VERSION 5.7 ;
  NOWIREEXTENSIONATPIN ON ;
  DIVIDERCHAR "/" ;
  BUSBITCHARS "[]" ;
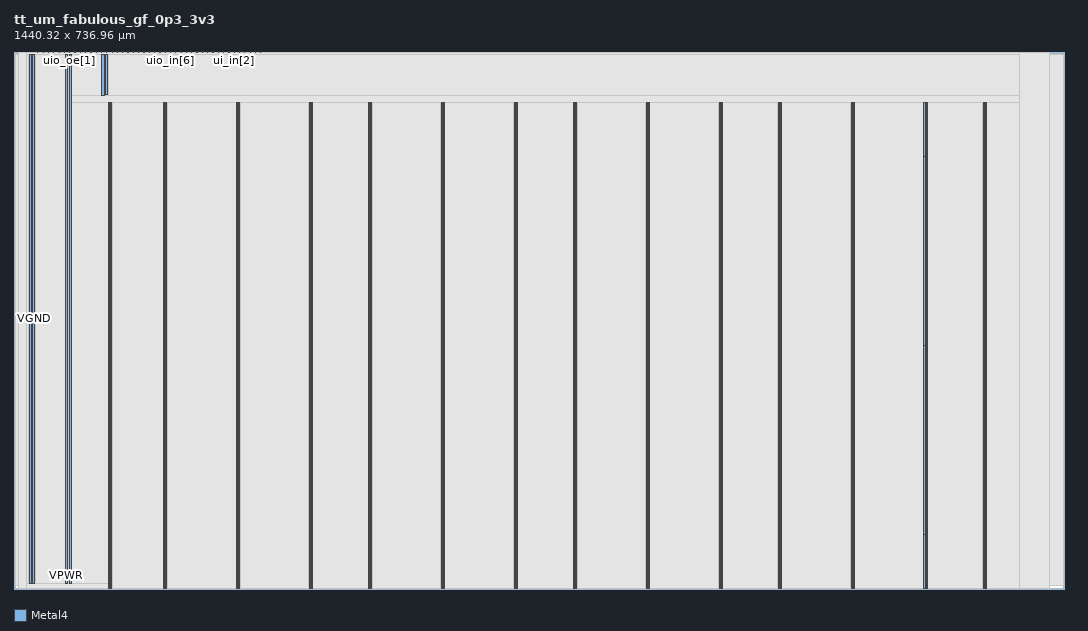
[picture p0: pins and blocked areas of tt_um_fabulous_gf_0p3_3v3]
MACRO tt_um_fabulous_gf_0p3_3v3
  CLASS BLOCK ;
  FOREIGN tt_um_fabulous_gf_0p3_3v3 ;
  ORIGIN 0.000 0.000 ;
  SIZE 1440.320 BY 736.960 ;
  PIN VGND
    DIRECTION INOUT ;
    USE GROUND ;
    PORT
      LAYER Metal4 ;
        RECT 132.580 592.600 134.180 667.080 ;
    END
    PORT
      LAYER Metal4 ;
        RECT 132.580 333.880 134.180 592.600 ;
    END
    PORT
      LAYER Metal4 ;
        RECT 132.580 75.160 134.180 333.880 ;
    END
    PORT
      LAYER Metal4 ;
        RECT 132.580 0.680 134.180 75.160 ;
    END
    PORT
      LAYER Metal4 ;
        RECT 208.180 592.600 209.780 667.080 ;
    END
    PORT
      LAYER Metal4 ;
        RECT 308.180 592.600 309.780 667.080 ;
    END
    PORT
      LAYER Metal4 ;
        RECT 408.180 592.600 409.780 667.080 ;
    END
    PORT
      LAYER Metal4 ;
        RECT 208.180 333.880 209.780 592.600 ;
    END
    PORT
      LAYER Metal4 ;
        RECT 308.180 333.880 309.780 592.600 ;
    END
    PORT
      LAYER Metal4 ;
        RECT 408.180 333.880 409.780 592.600 ;
    END
    PORT
      LAYER Metal4 ;
        RECT 208.180 75.160 209.780 333.880 ;
    END
    PORT
      LAYER Metal4 ;
        RECT 308.180 75.160 309.780 333.880 ;
    END
    PORT
      LAYER Metal4 ;
        RECT 408.180 75.160 409.780 333.880 ;
    END
    PORT
      LAYER Metal4 ;
        RECT 208.180 0.680 209.780 75.160 ;
    END
    PORT
      LAYER Metal4 ;
        RECT 308.180 0.680 309.780 75.160 ;
    END
    PORT
      LAYER Metal4 ;
        RECT 408.180 0.680 409.780 75.160 ;
    END
    PORT
      LAYER Metal4 ;
        RECT 489.300 592.600 490.900 667.080 ;
    END
    PORT
      LAYER Metal4 ;
        RECT 589.300 592.600 590.900 667.080 ;
    END
    PORT
      LAYER Metal4 ;
        RECT 689.300 592.600 690.900 667.080 ;
    END
    PORT
      LAYER Metal4 ;
        RECT 489.300 333.880 490.900 592.600 ;
    END
    PORT
      LAYER Metal4 ;
        RECT 589.300 333.880 590.900 592.600 ;
    END
    PORT
      LAYER Metal4 ;
        RECT 689.300 333.880 690.900 592.600 ;
    END
    PORT
      LAYER Metal4 ;
        RECT 489.300 75.160 490.900 333.880 ;
    END
    PORT
      LAYER Metal4 ;
        RECT 589.300 75.160 590.900 333.880 ;
    END
    PORT
      LAYER Metal4 ;
        RECT 689.300 75.160 690.900 333.880 ;
    END
    PORT
      LAYER Metal4 ;
        RECT 489.300 0.680 490.900 75.160 ;
    END
    PORT
      LAYER Metal4 ;
        RECT 589.300 0.680 590.900 75.160 ;
    END
    PORT
      LAYER Metal4 ;
        RECT 689.300 0.680 690.900 75.160 ;
    END
    PORT
      LAYER Metal4 ;
        RECT 770.420 592.600 772.020 667.080 ;
    END
    PORT
      LAYER Metal4 ;
        RECT 870.420 592.600 872.020 667.080 ;
    END
    PORT
      LAYER Metal4 ;
        RECT 970.420 592.600 972.020 667.080 ;
    END
    PORT
      LAYER Metal4 ;
        RECT 770.420 333.880 772.020 592.600 ;
    END
    PORT
      LAYER Metal4 ;
        RECT 870.420 333.880 872.020 592.600 ;
    END
    PORT
      LAYER Metal4 ;
        RECT 970.420 333.880 972.020 592.600 ;
    END
    PORT
      LAYER Metal4 ;
        RECT 770.420 75.160 772.020 333.880 ;
    END
    PORT
      LAYER Metal4 ;
        RECT 870.420 75.160 872.020 333.880 ;
    END
    PORT
      LAYER Metal4 ;
        RECT 970.420 75.160 972.020 333.880 ;
    END
    PORT
      LAYER Metal4 ;
        RECT 770.420 0.680 772.020 75.160 ;
    END
    PORT
      LAYER Metal4 ;
        RECT 870.420 0.680 872.020 75.160 ;
    END
    PORT
      LAYER Metal4 ;
        RECT 970.420 0.680 972.020 75.160 ;
    END
    PORT
      LAYER Metal4 ;
        RECT 1051.540 592.600 1053.140 667.080 ;
    END
    PORT
      LAYER Metal4 ;
        RECT 1151.540 592.600 1153.140 667.080 ;
    END
    PORT
      LAYER Metal4 ;
        RECT 1251.540 592.600 1253.140 667.080 ;
    END
    PORT
      LAYER Metal4 ;
        RECT 1051.540 333.880 1053.140 592.600 ;
    END
    PORT
      LAYER Metal4 ;
        RECT 1151.540 333.880 1153.140 592.600 ;
    END
    PORT
      LAYER Metal4 ;
        RECT 1251.540 333.880 1253.140 592.600 ;
    END
    PORT
      LAYER Metal4 ;
        RECT 1051.540 75.160 1053.140 333.880 ;
    END
    PORT
      LAYER Metal4 ;
        RECT 1151.540 75.160 1153.140 333.880 ;
    END
    PORT
      LAYER Metal4 ;
        RECT 1251.540 75.160 1253.140 333.880 ;
    END
    PORT
      LAYER Metal4 ;
        RECT 1051.540 0.680 1053.140 75.160 ;
    END
    PORT
      LAYER Metal4 ;
        RECT 1151.540 0.680 1153.140 75.160 ;
    END
    PORT
      LAYER Metal4 ;
        RECT 1251.540 0.680 1253.140 75.160 ;
    END
    PORT
      LAYER Metal4 ;
        RECT 1332.660 592.600 1334.260 667.080 ;
    END
    PORT
      LAYER Metal4 ;
        RECT 1332.660 333.880 1334.260 592.600 ;
    END
    PORT
      LAYER Metal4 ;
        RECT 1332.660 75.160 1334.260 333.880 ;
    END
    PORT
      LAYER Metal4 ;
        RECT 1332.660 0.680 1334.260 75.160 ;
    END
    PORT
      LAYER Metal4 ;
        RECT 25.540 7.540 28.740 733.340 ;
    END
    PORT
      LAYER Metal4 ;
        RECT 75.540 7.540 78.740 733.340 ;
    END
    PORT
      LAYER Metal4 ;
        RECT 125.540 677.640 128.740 733.340 ;
    END
  END VGND
  PIN VPWR
    DIRECTION INOUT ;
    USE POWER ;
    PORT
      LAYER Metal4 ;
        RECT 129.280 592.600 130.880 667.080 ;
    END
    PORT
      LAYER Metal4 ;
        RECT 129.280 333.880 130.880 592.600 ;
    END
    PORT
      LAYER Metal4 ;
        RECT 129.280 75.160 130.880 333.880 ;
    END
    PORT
      LAYER Metal4 ;
        RECT 129.280 0.680 130.880 75.160 ;
    END
    PORT
      LAYER Metal4 ;
        RECT 204.880 592.600 206.480 667.080 ;
    END
    PORT
      LAYER Metal4 ;
        RECT 304.880 592.600 306.480 667.080 ;
    END
    PORT
      LAYER Metal4 ;
        RECT 404.880 592.600 406.480 667.080 ;
    END
    PORT
      LAYER Metal4 ;
        RECT 204.880 333.880 206.480 592.600 ;
    END
    PORT
      LAYER Metal4 ;
        RECT 304.880 333.880 306.480 592.600 ;
    END
    PORT
      LAYER Metal4 ;
        RECT 404.880 333.880 406.480 592.600 ;
    END
    PORT
      LAYER Metal4 ;
        RECT 204.880 75.160 206.480 333.880 ;
    END
    PORT
      LAYER Metal4 ;
        RECT 304.880 75.160 306.480 333.880 ;
    END
    PORT
      LAYER Metal4 ;
        RECT 404.880 75.160 406.480 333.880 ;
    END
    PORT
      LAYER Metal4 ;
        RECT 204.880 0.680 206.480 75.160 ;
    END
    PORT
      LAYER Metal4 ;
        RECT 304.880 0.680 306.480 75.160 ;
    END
    PORT
      LAYER Metal4 ;
        RECT 404.880 0.680 406.480 75.160 ;
    END
    PORT
      LAYER Metal4 ;
        RECT 486.000 592.600 487.600 667.080 ;
    END
    PORT
      LAYER Metal4 ;
        RECT 586.000 592.600 587.600 667.080 ;
    END
    PORT
      LAYER Metal4 ;
        RECT 686.000 592.600 687.600 667.080 ;
    END
    PORT
      LAYER Metal4 ;
        RECT 486.000 333.880 487.600 592.600 ;
    END
    PORT
      LAYER Metal4 ;
        RECT 586.000 333.880 587.600 592.600 ;
    END
    PORT
      LAYER Metal4 ;
        RECT 686.000 333.880 687.600 592.600 ;
    END
    PORT
      LAYER Metal4 ;
        RECT 486.000 75.160 487.600 333.880 ;
    END
    PORT
      LAYER Metal4 ;
        RECT 586.000 75.160 587.600 333.880 ;
    END
    PORT
      LAYER Metal4 ;
        RECT 686.000 75.160 687.600 333.880 ;
    END
    PORT
      LAYER Metal4 ;
        RECT 486.000 0.680 487.600 75.160 ;
    END
    PORT
      LAYER Metal4 ;
        RECT 586.000 0.680 587.600 75.160 ;
    END
    PORT
      LAYER Metal4 ;
        RECT 686.000 0.680 687.600 75.160 ;
    END
    PORT
      LAYER Metal4 ;
        RECT 767.120 592.600 768.720 667.080 ;
    END
    PORT
      LAYER Metal4 ;
        RECT 867.120 592.600 868.720 667.080 ;
    END
    PORT
      LAYER Metal4 ;
        RECT 967.120 592.600 968.720 667.080 ;
    END
    PORT
      LAYER Metal4 ;
        RECT 767.120 333.880 768.720 592.600 ;
    END
    PORT
      LAYER Metal4 ;
        RECT 867.120 333.880 868.720 592.600 ;
    END
    PORT
      LAYER Metal4 ;
        RECT 967.120 333.880 968.720 592.600 ;
    END
    PORT
      LAYER Metal4 ;
        RECT 767.120 75.160 768.720 333.880 ;
    END
    PORT
      LAYER Metal4 ;
        RECT 867.120 75.160 868.720 333.880 ;
    END
    PORT
      LAYER Metal4 ;
        RECT 967.120 75.160 968.720 333.880 ;
    END
    PORT
      LAYER Metal4 ;
        RECT 767.120 0.680 768.720 75.160 ;
    END
    PORT
      LAYER Metal4 ;
        RECT 867.120 0.680 868.720 75.160 ;
    END
    PORT
      LAYER Metal4 ;
        RECT 967.120 0.680 968.720 75.160 ;
    END
    PORT
      LAYER Metal4 ;
        RECT 1048.240 592.600 1049.840 667.080 ;
    END
    PORT
      LAYER Metal4 ;
        RECT 1148.240 592.600 1149.840 667.080 ;
    END
    PORT
      LAYER Metal4 ;
        RECT 1248.240 592.600 1249.840 667.080 ;
    END
    PORT
      LAYER Metal4 ;
        RECT 1048.240 333.880 1049.840 592.600 ;
    END
    PORT
      LAYER Metal4 ;
        RECT 1148.240 333.880 1149.840 592.600 ;
    END
    PORT
      LAYER Metal4 ;
        RECT 1248.240 333.880 1249.840 592.600 ;
    END
    PORT
      LAYER Metal4 ;
        RECT 1048.240 75.160 1049.840 333.880 ;
    END
    PORT
      LAYER Metal4 ;
        RECT 1148.240 75.160 1149.840 333.880 ;
    END
    PORT
      LAYER Metal4 ;
        RECT 1248.240 75.160 1249.840 333.880 ;
    END
    PORT
      LAYER Metal4 ;
        RECT 1048.240 0.680 1049.840 75.160 ;
    END
    PORT
      LAYER Metal4 ;
        RECT 1148.240 0.680 1149.840 75.160 ;
    END
    PORT
      LAYER Metal4 ;
        RECT 1248.240 0.680 1249.840 75.160 ;
    END
    PORT
      LAYER Metal4 ;
        RECT 1329.360 592.600 1330.960 667.080 ;
    END
    PORT
      LAYER Metal4 ;
        RECT 1329.360 333.880 1330.960 592.600 ;
    END
    PORT
      LAYER Metal4 ;
        RECT 1329.360 75.160 1330.960 333.880 ;
    END
    PORT
      LAYER Metal4 ;
        RECT 1329.360 0.680 1330.960 75.160 ;
    END
    PORT
      LAYER Metal4 ;
        RECT 20.640 7.540 23.840 733.340 ;
    END
    PORT
      LAYER Metal4 ;
        RECT 70.640 7.540 73.840 733.340 ;
    END
    PORT
      LAYER Metal4 ;
        RECT 120.640 676.710 123.840 733.340 ;
    END
  END VPWR
  PIN clk
    DIRECTION INPUT ;
    USE SIGNAL ;
    ANTENNAGATEAREA 4.704000 ;
    ANTENNADIFFAREA 0.877000 ;
    PORT
      LAYER Metal4 ;
        RECT 331.090 735.960 331.390 736.960 ;
    END
  END clk
  PIN ena
    DIRECTION INPUT ;
    USE SIGNAL ;
    PORT
      LAYER Metal4 ;
        RECT 338.370 735.960 338.670 736.960 ;
    END
  END ena
  PIN rst_n
    DIRECTION INPUT ;
    USE SIGNAL ;
    ANTENNAGATEAREA 0.666400 ;
    ANTENNADIFFAREA 0.438500 ;
    PORT
      LAYER Metal4 ;
        RECT 323.810 735.960 324.110 736.960 ;
    END
  END rst_n
  PIN ui_in[0]
    DIRECTION INPUT ;
    USE SIGNAL ;
    ANTENNAGATEAREA 0.666400 ;
    ANTENNADIFFAREA 0.438500 ;
    PORT
      LAYER Metal4 ;
        RECT 316.530 735.960 316.830 736.960 ;
    END
  END ui_in[0]
  PIN ui_in[1]
    DIRECTION INPUT ;
    USE SIGNAL ;
    ANTENNAGATEAREA 0.666400 ;
    ANTENNADIFFAREA 0.438500 ;
    PORT
      LAYER Metal4 ;
        RECT 309.250 735.960 309.550 736.960 ;
    END
  END ui_in[1]
  PIN ui_in[2]
    DIRECTION INPUT ;
    USE SIGNAL ;
    ANTENNAGATEAREA 1.332800 ;
    ANTENNADIFFAREA 0.438500 ;
    PORT
      LAYER Metal4 ;
        RECT 301.970 735.960 302.270 736.960 ;
    END
  END ui_in[2]
  PIN ui_in[3]
    DIRECTION INPUT ;
    USE SIGNAL ;
    ANTENNAGATEAREA 1.332800 ;
    ANTENNADIFFAREA 0.438500 ;
    PORT
      LAYER Metal4 ;
        RECT 294.690 735.960 294.990 736.960 ;
    END
  END ui_in[3]
  PIN ui_in[4]
    DIRECTION INPUT ;
    USE SIGNAL ;
    ANTENNAGATEAREA 1.332800 ;
    ANTENNADIFFAREA 0.438500 ;
    PORT
      LAYER Metal4 ;
        RECT 287.410 735.960 287.710 736.960 ;
    END
  END ui_in[4]
  PIN ui_in[5]
    DIRECTION INPUT ;
    USE SIGNAL ;
    ANTENNAGATEAREA 1.332800 ;
    ANTENNADIFFAREA 0.438500 ;
    PORT
      LAYER Metal4 ;
        RECT 280.130 735.960 280.430 736.960 ;
    END
  END ui_in[5]
  PIN ui_in[6]
    DIRECTION INPUT ;
    USE SIGNAL ;
    ANTENNAGATEAREA 1.332800 ;
    ANTENNADIFFAREA 0.438500 ;
    PORT
      LAYER Metal4 ;
        RECT 272.850 735.960 273.150 736.960 ;
    END
  END ui_in[6]
  PIN ui_in[7]
    DIRECTION INPUT ;
    USE SIGNAL ;
    ANTENNAGATEAREA 1.332800 ;
    ANTENNADIFFAREA 0.438500 ;
    PORT
      LAYER Metal4 ;
        RECT 265.570 735.960 265.870 736.960 ;
    END
  END ui_in[7]
  PIN uio_in[0]
    DIRECTION INPUT ;
    USE SIGNAL ;
    ANTENNAGATEAREA 1.332800 ;
    ANTENNADIFFAREA 0.438500 ;
    PORT
      LAYER Metal4 ;
        RECT 258.290 735.960 258.590 736.960 ;
    END
  END uio_in[0]
  PIN uio_in[1]
    DIRECTION INPUT ;
    USE SIGNAL ;
    ANTENNAGATEAREA 1.332800 ;
    ANTENNADIFFAREA 0.438500 ;
    PORT
      LAYER Metal4 ;
        RECT 251.010 735.960 251.310 736.960 ;
    END
  END uio_in[1]
  PIN uio_in[2]
    DIRECTION INPUT ;
    USE SIGNAL ;
    ANTENNAGATEAREA 1.332800 ;
    ANTENNADIFFAREA 0.438500 ;
    PORT
      LAYER Metal4 ;
        RECT 243.730 735.960 244.030 736.960 ;
    END
  END uio_in[2]
  PIN uio_in[3]
    DIRECTION INPUT ;
    USE SIGNAL ;
    ANTENNAGATEAREA 1.332800 ;
    ANTENNADIFFAREA 0.438500 ;
    PORT
      LAYER Metal4 ;
        RECT 236.450 735.960 236.750 736.960 ;
    END
  END uio_in[3]
  PIN uio_in[4]
    DIRECTION INPUT ;
    USE SIGNAL ;
    ANTENNAGATEAREA 1.332800 ;
    ANTENNADIFFAREA 0.438500 ;
    PORT
      LAYER Metal4 ;
        RECT 229.170 735.960 229.470 736.960 ;
    END
  END uio_in[4]
  PIN uio_in[5]
    DIRECTION INPUT ;
    USE SIGNAL ;
    ANTENNAGATEAREA 1.332800 ;
    ANTENNADIFFAREA 0.438500 ;
    PORT
      LAYER Metal4 ;
        RECT 221.890 735.960 222.190 736.960 ;
    END
  END uio_in[5]
  PIN uio_in[6]
    DIRECTION INPUT ;
    USE SIGNAL ;
    ANTENNAGATEAREA 1.332800 ;
    ANTENNADIFFAREA 0.438500 ;
    PORT
      LAYER Metal4 ;
        RECT 214.610 735.960 214.910 736.960 ;
    END
  END uio_in[6]
  PIN uio_in[7]
    DIRECTION INPUT ;
    USE SIGNAL ;
    ANTENNAGATEAREA 1.332800 ;
    ANTENNADIFFAREA 0.438500 ;
    PORT
      LAYER Metal4 ;
        RECT 207.330 735.960 207.630 736.960 ;
    END
  END uio_in[7]
  PIN uio_oe[0]
    DIRECTION OUTPUT ;
    USE SIGNAL ;
    ANTENNADIFFAREA 1.676100 ;
    PORT
      LAYER Metal4 ;
        RECT 83.570 735.960 83.870 736.960 ;
    END
  END uio_oe[0]
  PIN uio_oe[1]
    DIRECTION OUTPUT ;
    USE SIGNAL ;
    ANTENNADIFFAREA 1.676100 ;
    PORT
      LAYER Metal4 ;
        RECT 76.290 735.960 76.590 736.960 ;
    END
  END uio_oe[1]
  PIN uio_oe[2]
    DIRECTION OUTPUT ;
    USE SIGNAL ;
    ANTENNADIFFAREA 1.676100 ;
    PORT
      LAYER Metal4 ;
        RECT 69.010 735.960 69.310 736.960 ;
    END
  END uio_oe[2]
  PIN uio_oe[3]
    DIRECTION OUTPUT ;
    USE SIGNAL ;
    ANTENNADIFFAREA 1.676100 ;
    PORT
      LAYER Metal4 ;
        RECT 61.730 735.960 62.030 736.960 ;
    END
  END uio_oe[3]
  PIN uio_oe[4]
    DIRECTION OUTPUT ;
    USE SIGNAL ;
    ANTENNADIFFAREA 1.676100 ;
    PORT
      LAYER Metal4 ;
        RECT 54.450 735.960 54.750 736.960 ;
    END
  END uio_oe[4]
  PIN uio_oe[5]
    DIRECTION OUTPUT ;
    USE SIGNAL ;
    ANTENNADIFFAREA 1.676100 ;
    PORT
      LAYER Metal4 ;
        RECT 47.170 735.960 47.470 736.960 ;
    END
  END uio_oe[5]
  PIN uio_oe[6]
    DIRECTION OUTPUT ;
    USE SIGNAL ;
    ANTENNADIFFAREA 1.676100 ;
    PORT
      LAYER Metal4 ;
        RECT 39.890 735.960 40.190 736.960 ;
    END
  END uio_oe[6]
  PIN uio_oe[7]
    DIRECTION OUTPUT ;
    USE SIGNAL ;
    ANTENNADIFFAREA 1.676100 ;
    PORT
      LAYER Metal4 ;
        RECT 32.610 735.960 32.910 736.960 ;
    END
  END uio_oe[7]
  PIN uio_out[0]
    DIRECTION OUTPUT ;
    USE SIGNAL ;
    ANTENNADIFFAREA 1.676100 ;
    PORT
      LAYER Metal4 ;
        RECT 141.810 735.960 142.110 736.960 ;
    END
  END uio_out[0]
  PIN uio_out[1]
    DIRECTION OUTPUT ;
    USE SIGNAL ;
    ANTENNADIFFAREA 1.676100 ;
    PORT
      LAYER Metal4 ;
        RECT 134.530 735.960 134.830 736.960 ;
    END
  END uio_out[1]
  PIN uio_out[2]
    DIRECTION OUTPUT ;
    USE SIGNAL ;
    ANTENNADIFFAREA 1.676100 ;
    PORT
      LAYER Metal4 ;
        RECT 127.250 735.960 127.550 736.960 ;
    END
  END uio_out[2]
  PIN uio_out[3]
    DIRECTION OUTPUT ;
    USE SIGNAL ;
    ANTENNADIFFAREA 1.676100 ;
    PORT
      LAYER Metal4 ;
        RECT 119.970 735.960 120.270 736.960 ;
    END
  END uio_out[3]
  PIN uio_out[4]
    DIRECTION OUTPUT ;
    USE SIGNAL ;
    ANTENNADIFFAREA 1.676100 ;
    PORT
      LAYER Metal4 ;
        RECT 112.690 735.960 112.990 736.960 ;
    END
  END uio_out[4]
  PIN uio_out[5]
    DIRECTION OUTPUT ;
    USE SIGNAL ;
    ANTENNADIFFAREA 1.676100 ;
    PORT
      LAYER Metal4 ;
        RECT 105.410 735.960 105.710 736.960 ;
    END
  END uio_out[5]
  PIN uio_out[6]
    DIRECTION OUTPUT ;
    USE SIGNAL ;
    ANTENNADIFFAREA 1.676100 ;
    PORT
      LAYER Metal4 ;
        RECT 98.130 735.960 98.430 736.960 ;
    END
  END uio_out[6]
  PIN uio_out[7]
    DIRECTION OUTPUT ;
    USE SIGNAL ;
    ANTENNADIFFAREA 1.676100 ;
    PORT
      LAYER Metal4 ;
        RECT 90.850 735.960 91.150 736.960 ;
    END
  END uio_out[7]
  PIN uo_out[0]
    DIRECTION OUTPUT ;
    USE SIGNAL ;
    ANTENNADIFFAREA 5.982500 ;
    PORT
      LAYER Metal4 ;
        RECT 200.050 735.960 200.350 736.960 ;
    END
  END uo_out[0]
  PIN uo_out[1]
    DIRECTION OUTPUT ;
    USE SIGNAL ;
    ANTENNADIFFAREA 5.982500 ;
    PORT
      LAYER Metal4 ;
        RECT 192.770 735.960 193.070 736.960 ;
    END
  END uo_out[1]
  PIN uo_out[2]
    DIRECTION OUTPUT ;
    USE SIGNAL ;
    ANTENNADIFFAREA 5.982500 ;
    PORT
      LAYER Metal4 ;
        RECT 185.490 735.960 185.790 736.960 ;
    END
  END uo_out[2]
  PIN uo_out[3]
    DIRECTION OUTPUT ;
    USE SIGNAL ;
    ANTENNADIFFAREA 5.982500 ;
    PORT
      LAYER Metal4 ;
        RECT 178.210 735.960 178.510 736.960 ;
    END
  END uo_out[3]
  PIN uo_out[4]
    DIRECTION OUTPUT ;
    USE SIGNAL ;
    ANTENNADIFFAREA 5.982500 ;
    PORT
      LAYER Metal4 ;
        RECT 170.930 735.960 171.230 736.960 ;
    END
  END uo_out[4]
  PIN uo_out[5]
    DIRECTION OUTPUT ;
    USE SIGNAL ;
    ANTENNADIFFAREA 5.982500 ;
    PORT
      LAYER Metal4 ;
        RECT 163.650 735.960 163.950 736.960 ;
    END
  END uo_out[5]
  PIN uo_out[6]
    DIRECTION OUTPUT ;
    USE SIGNAL ;
    ANTENNADIFFAREA 5.982500 ;
    PORT
      LAYER Metal4 ;
        RECT 156.370 735.960 156.670 736.960 ;
    END
  END uo_out[6]
  PIN uo_out[7]
    DIRECTION OUTPUT ;
    USE SIGNAL ;
    ANTENNADIFFAREA 5.982500 ;
    PORT
      LAYER Metal4 ;
        RECT 149.090 735.960 149.390 736.960 ;
    END
  END uo_out[7]
  OBS
      LAYER Nwell ;
        RECT 1.810 730.890 1440.190 733.470 ;
      LAYER Pwell ;
        RECT 1.810 727.350 1440.190 730.890 ;
      LAYER Nwell ;
        RECT 1.810 723.050 1440.190 727.350 ;
      LAYER Pwell ;
        RECT 1.810 719.510 1440.190 723.050 ;
      LAYER Nwell ;
        RECT 1.810 715.210 1440.190 719.510 ;
      LAYER Pwell ;
        RECT 1.810 711.670 1440.190 715.210 ;
      LAYER Nwell ;
        RECT 1.810 707.370 1440.190 711.670 ;
      LAYER Pwell ;
        RECT 1.810 703.830 1440.190 707.370 ;
      LAYER Nwell ;
        RECT 1.810 699.530 1440.190 703.830 ;
      LAYER Pwell ;
        RECT 1.810 695.990 1440.190 699.530 ;
      LAYER Nwell ;
        RECT 1.810 691.690 1440.190 695.990 ;
      LAYER Pwell ;
        RECT 1.810 688.150 1440.190 691.690 ;
      LAYER Nwell ;
        RECT 1.810 683.850 1440.190 688.150 ;
      LAYER Pwell ;
        RECT 1.810 680.310 1440.190 683.850 ;
      LAYER Nwell ;
        RECT 1.810 676.010 1440.190 680.310 ;
      LAYER Pwell ;
        RECT 1.810 673.810 1440.190 676.010 ;
        RECT 1.810 672.470 106.270 673.810 ;
      LAYER Nwell ;
        RECT 106.270 672.470 1440.190 673.810 ;
        RECT 1.810 668.170 1440.190 672.470 ;
      LAYER Pwell ;
        RECT 1.810 664.630 106.270 668.170 ;
      LAYER Nwell ;
        RECT 106.270 664.630 1440.190 668.170 ;
        RECT 1.810 660.330 1440.190 664.630 ;
      LAYER Pwell ;
        RECT 1.810 656.790 106.270 660.330 ;
      LAYER Nwell ;
        RECT 106.270 656.790 1440.190 660.330 ;
        RECT 1.810 652.490 1440.190 656.790 ;
      LAYER Pwell ;
        RECT 1.810 648.950 106.270 652.490 ;
      LAYER Nwell ;
        RECT 106.270 648.950 1440.190 652.490 ;
        RECT 1.810 644.650 1440.190 648.950 ;
      LAYER Pwell ;
        RECT 1.810 641.110 106.270 644.650 ;
      LAYER Nwell ;
        RECT 106.270 641.110 1440.190 644.650 ;
        RECT 1.810 636.810 1440.190 641.110 ;
      LAYER Pwell ;
        RECT 1.810 633.270 106.270 636.810 ;
      LAYER Nwell ;
        RECT 106.270 633.270 1440.190 636.810 ;
        RECT 1.810 628.970 1440.190 633.270 ;
      LAYER Pwell ;
        RECT 1.810 625.430 106.270 628.970 ;
      LAYER Nwell ;
        RECT 106.270 625.430 1440.190 628.970 ;
        RECT 1.810 621.130 1440.190 625.430 ;
      LAYER Pwell ;
        RECT 1.810 617.590 106.270 621.130 ;
      LAYER Nwell ;
        RECT 106.270 617.590 1440.190 621.130 ;
        RECT 1.810 613.290 1440.190 617.590 ;
      LAYER Pwell ;
        RECT 1.810 609.750 106.270 613.290 ;
      LAYER Nwell ;
        RECT 106.270 609.750 1440.190 613.290 ;
        RECT 1.810 605.450 1440.190 609.750 ;
      LAYER Pwell ;
        RECT 1.810 601.910 106.270 605.450 ;
      LAYER Nwell ;
        RECT 106.270 601.910 1440.190 605.450 ;
        RECT 1.810 597.610 1440.190 601.910 ;
      LAYER Pwell ;
        RECT 1.810 594.070 106.270 597.610 ;
      LAYER Nwell ;
        RECT 106.270 594.070 1440.190 597.610 ;
        RECT 1.810 589.770 1440.190 594.070 ;
      LAYER Pwell ;
        RECT 1.810 586.230 106.270 589.770 ;
      LAYER Nwell ;
        RECT 106.270 586.230 1440.190 589.770 ;
        RECT 1.810 581.930 1440.190 586.230 ;
      LAYER Pwell ;
        RECT 1.810 578.390 106.270 581.930 ;
      LAYER Nwell ;
        RECT 106.270 578.390 1440.190 581.930 ;
        RECT 1.810 574.090 1440.190 578.390 ;
      LAYER Pwell ;
        RECT 1.810 570.550 106.270 574.090 ;
      LAYER Nwell ;
        RECT 106.270 570.550 1440.190 574.090 ;
        RECT 1.810 566.250 1440.190 570.550 ;
      LAYER Pwell ;
        RECT 1.810 562.710 106.270 566.250 ;
      LAYER Nwell ;
        RECT 106.270 562.710 1440.190 566.250 ;
        RECT 1.810 558.410 1440.190 562.710 ;
      LAYER Pwell ;
        RECT 1.810 554.870 106.270 558.410 ;
      LAYER Nwell ;
        RECT 106.270 554.870 1440.190 558.410 ;
        RECT 1.810 550.570 1440.190 554.870 ;
      LAYER Pwell ;
        RECT 1.810 547.030 106.270 550.570 ;
      LAYER Nwell ;
        RECT 106.270 547.030 1440.190 550.570 ;
        RECT 1.810 542.730 1440.190 547.030 ;
      LAYER Pwell ;
        RECT 1.810 539.190 106.270 542.730 ;
      LAYER Nwell ;
        RECT 106.270 539.190 1440.190 542.730 ;
        RECT 1.810 534.890 1440.190 539.190 ;
      LAYER Pwell ;
        RECT 1.810 531.350 106.270 534.890 ;
      LAYER Nwell ;
        RECT 106.270 531.350 1440.190 534.890 ;
        RECT 1.810 527.050 1440.190 531.350 ;
      LAYER Pwell ;
        RECT 1.810 523.510 106.270 527.050 ;
      LAYER Nwell ;
        RECT 106.270 523.510 1440.190 527.050 ;
        RECT 1.810 519.210 1440.190 523.510 ;
      LAYER Pwell ;
        RECT 1.810 515.670 106.270 519.210 ;
      LAYER Nwell ;
        RECT 106.270 515.670 1440.190 519.210 ;
        RECT 1.810 511.370 1440.190 515.670 ;
      LAYER Pwell ;
        RECT 1.810 507.830 106.270 511.370 ;
      LAYER Nwell ;
        RECT 106.270 507.830 1440.190 511.370 ;
        RECT 1.810 503.530 1440.190 507.830 ;
      LAYER Pwell ;
        RECT 1.810 499.990 106.270 503.530 ;
      LAYER Nwell ;
        RECT 106.270 499.990 1440.190 503.530 ;
        RECT 1.810 495.690 1440.190 499.990 ;
      LAYER Pwell ;
        RECT 1.810 492.150 106.270 495.690 ;
      LAYER Nwell ;
        RECT 106.270 492.150 1440.190 495.690 ;
        RECT 1.810 487.850 1440.190 492.150 ;
      LAYER Pwell ;
        RECT 1.810 484.310 106.270 487.850 ;
      LAYER Nwell ;
        RECT 106.270 484.310 1440.190 487.850 ;
        RECT 1.810 480.010 1440.190 484.310 ;
      LAYER Pwell ;
        RECT 1.810 476.470 106.270 480.010 ;
      LAYER Nwell ;
        RECT 106.270 476.470 1440.190 480.010 ;
        RECT 1.810 472.170 1440.190 476.470 ;
      LAYER Pwell ;
        RECT 1.810 468.630 106.270 472.170 ;
      LAYER Nwell ;
        RECT 106.270 468.630 1440.190 472.170 ;
        RECT 1.810 464.330 1440.190 468.630 ;
      LAYER Pwell ;
        RECT 1.810 460.790 106.270 464.330 ;
      LAYER Nwell ;
        RECT 106.270 460.790 1440.190 464.330 ;
        RECT 1.810 456.490 1440.190 460.790 ;
      LAYER Pwell ;
        RECT 1.810 452.950 106.270 456.490 ;
      LAYER Nwell ;
        RECT 106.270 452.950 1440.190 456.490 ;
        RECT 1.810 448.650 1440.190 452.950 ;
      LAYER Pwell ;
        RECT 1.810 445.110 106.270 448.650 ;
      LAYER Nwell ;
        RECT 106.270 445.110 1440.190 448.650 ;
        RECT 1.810 440.810 1440.190 445.110 ;
      LAYER Pwell ;
        RECT 1.810 437.270 106.270 440.810 ;
      LAYER Nwell ;
        RECT 106.270 437.270 1440.190 440.810 ;
        RECT 1.810 432.970 1440.190 437.270 ;
      LAYER Pwell ;
        RECT 1.810 429.430 106.270 432.970 ;
      LAYER Nwell ;
        RECT 106.270 429.430 1440.190 432.970 ;
        RECT 1.810 425.130 1440.190 429.430 ;
      LAYER Pwell ;
        RECT 1.810 421.590 106.270 425.130 ;
      LAYER Nwell ;
        RECT 106.270 421.590 1440.190 425.130 ;
        RECT 1.810 417.290 1440.190 421.590 ;
      LAYER Pwell ;
        RECT 1.810 413.750 106.270 417.290 ;
      LAYER Nwell ;
        RECT 106.270 413.750 1440.190 417.290 ;
        RECT 1.810 409.450 1440.190 413.750 ;
      LAYER Pwell ;
        RECT 1.810 405.910 106.270 409.450 ;
      LAYER Nwell ;
        RECT 106.270 405.910 1440.190 409.450 ;
        RECT 1.810 401.610 1440.190 405.910 ;
      LAYER Pwell ;
        RECT 1.810 398.070 106.270 401.610 ;
      LAYER Nwell ;
        RECT 106.270 398.070 1440.190 401.610 ;
        RECT 1.810 393.770 1440.190 398.070 ;
      LAYER Pwell ;
        RECT 1.810 390.230 106.270 393.770 ;
      LAYER Nwell ;
        RECT 106.270 390.230 1440.190 393.770 ;
        RECT 1.810 385.930 1440.190 390.230 ;
      LAYER Pwell ;
        RECT 1.810 382.390 106.270 385.930 ;
      LAYER Nwell ;
        RECT 106.270 382.390 1440.190 385.930 ;
        RECT 1.810 378.090 1440.190 382.390 ;
      LAYER Pwell ;
        RECT 1.810 374.550 106.270 378.090 ;
      LAYER Nwell ;
        RECT 106.270 374.550 1440.190 378.090 ;
        RECT 1.810 370.250 1440.190 374.550 ;
      LAYER Pwell ;
        RECT 1.810 366.710 106.270 370.250 ;
      LAYER Nwell ;
        RECT 106.270 366.710 1440.190 370.250 ;
        RECT 1.810 362.410 1440.190 366.710 ;
      LAYER Pwell ;
        RECT 1.810 358.870 106.270 362.410 ;
      LAYER Nwell ;
        RECT 106.270 358.870 1440.190 362.410 ;
        RECT 1.810 354.570 1440.190 358.870 ;
      LAYER Pwell ;
        RECT 1.810 351.030 106.270 354.570 ;
      LAYER Nwell ;
        RECT 106.270 351.030 1440.190 354.570 ;
        RECT 1.810 346.730 1440.190 351.030 ;
      LAYER Pwell ;
        RECT 1.810 343.190 106.270 346.730 ;
      LAYER Nwell ;
        RECT 106.270 343.190 1440.190 346.730 ;
        RECT 1.810 338.890 1440.190 343.190 ;
      LAYER Pwell ;
        RECT 1.810 335.350 106.270 338.890 ;
      LAYER Nwell ;
        RECT 106.270 335.350 1440.190 338.890 ;
        RECT 1.810 331.050 1440.190 335.350 ;
      LAYER Pwell ;
        RECT 1.810 327.510 106.270 331.050 ;
      LAYER Nwell ;
        RECT 106.270 327.510 1440.190 331.050 ;
        RECT 1.810 323.210 1440.190 327.510 ;
      LAYER Pwell ;
        RECT 1.810 319.670 106.270 323.210 ;
      LAYER Nwell ;
        RECT 106.270 319.670 1440.190 323.210 ;
        RECT 1.810 315.370 1440.190 319.670 ;
      LAYER Pwell ;
        RECT 1.810 311.830 106.270 315.370 ;
      LAYER Nwell ;
        RECT 106.270 311.830 1440.190 315.370 ;
        RECT 1.810 307.530 1440.190 311.830 ;
      LAYER Pwell ;
        RECT 1.810 303.990 106.270 307.530 ;
      LAYER Nwell ;
        RECT 106.270 303.990 1440.190 307.530 ;
        RECT 1.810 299.690 1440.190 303.990 ;
      LAYER Pwell ;
        RECT 1.810 296.150 106.270 299.690 ;
      LAYER Nwell ;
        RECT 106.270 296.150 1440.190 299.690 ;
        RECT 1.810 291.850 1440.190 296.150 ;
      LAYER Pwell ;
        RECT 1.810 288.310 106.270 291.850 ;
      LAYER Nwell ;
        RECT 106.270 288.310 1440.190 291.850 ;
        RECT 1.810 284.010 1440.190 288.310 ;
      LAYER Pwell ;
        RECT 1.810 280.470 106.270 284.010 ;
      LAYER Nwell ;
        RECT 106.270 280.470 1440.190 284.010 ;
        RECT 1.810 276.170 1440.190 280.470 ;
      LAYER Pwell ;
        RECT 1.810 272.630 106.270 276.170 ;
      LAYER Nwell ;
        RECT 106.270 272.630 1440.190 276.170 ;
        RECT 1.810 268.330 1440.190 272.630 ;
      LAYER Pwell ;
        RECT 1.810 264.790 106.270 268.330 ;
      LAYER Nwell ;
        RECT 106.270 264.790 1440.190 268.330 ;
        RECT 1.810 260.490 1440.190 264.790 ;
      LAYER Pwell ;
        RECT 1.810 256.950 106.270 260.490 ;
      LAYER Nwell ;
        RECT 106.270 256.950 1440.190 260.490 ;
        RECT 1.810 252.650 1440.190 256.950 ;
      LAYER Pwell ;
        RECT 1.810 249.110 106.270 252.650 ;
      LAYER Nwell ;
        RECT 106.270 249.110 1440.190 252.650 ;
        RECT 1.810 244.810 1440.190 249.110 ;
      LAYER Pwell ;
        RECT 1.810 241.270 106.270 244.810 ;
      LAYER Nwell ;
        RECT 106.270 241.270 1440.190 244.810 ;
        RECT 1.810 236.970 1440.190 241.270 ;
      LAYER Pwell ;
        RECT 1.810 233.430 106.270 236.970 ;
      LAYER Nwell ;
        RECT 106.270 233.430 1440.190 236.970 ;
        RECT 1.810 229.130 1440.190 233.430 ;
      LAYER Pwell ;
        RECT 1.810 225.590 106.270 229.130 ;
      LAYER Nwell ;
        RECT 106.270 225.590 1440.190 229.130 ;
        RECT 1.810 221.290 1440.190 225.590 ;
      LAYER Pwell ;
        RECT 1.810 217.750 106.270 221.290 ;
      LAYER Nwell ;
        RECT 106.270 217.750 1440.190 221.290 ;
        RECT 1.810 213.450 1440.190 217.750 ;
      LAYER Pwell ;
        RECT 1.810 209.910 106.270 213.450 ;
      LAYER Nwell ;
        RECT 106.270 209.910 1440.190 213.450 ;
        RECT 1.810 205.610 1440.190 209.910 ;
      LAYER Pwell ;
        RECT 1.810 202.070 106.270 205.610 ;
      LAYER Nwell ;
        RECT 106.270 202.070 1440.190 205.610 ;
        RECT 1.810 197.770 1440.190 202.070 ;
      LAYER Pwell ;
        RECT 1.810 194.230 106.270 197.770 ;
      LAYER Nwell ;
        RECT 106.270 194.230 1440.190 197.770 ;
        RECT 1.810 189.930 1440.190 194.230 ;
      LAYER Pwell ;
        RECT 1.810 186.390 106.270 189.930 ;
      LAYER Nwell ;
        RECT 106.270 186.390 1440.190 189.930 ;
        RECT 1.810 182.090 1440.190 186.390 ;
      LAYER Pwell ;
        RECT 1.810 178.550 106.270 182.090 ;
      LAYER Nwell ;
        RECT 106.270 178.550 1440.190 182.090 ;
        RECT 1.810 174.250 1440.190 178.550 ;
      LAYER Pwell ;
        RECT 1.810 170.710 106.270 174.250 ;
      LAYER Nwell ;
        RECT 106.270 170.710 1440.190 174.250 ;
        RECT 1.810 166.410 1440.190 170.710 ;
      LAYER Pwell ;
        RECT 1.810 162.870 106.270 166.410 ;
      LAYER Nwell ;
        RECT 106.270 162.870 1440.190 166.410 ;
        RECT 1.810 158.570 1440.190 162.870 ;
      LAYER Pwell ;
        RECT 1.810 155.030 106.270 158.570 ;
      LAYER Nwell ;
        RECT 106.270 155.030 1440.190 158.570 ;
        RECT 1.810 150.730 1440.190 155.030 ;
      LAYER Pwell ;
        RECT 1.810 147.190 106.270 150.730 ;
      LAYER Nwell ;
        RECT 106.270 147.190 1440.190 150.730 ;
        RECT 1.810 142.890 1440.190 147.190 ;
      LAYER Pwell ;
        RECT 1.810 139.350 106.270 142.890 ;
      LAYER Nwell ;
        RECT 106.270 139.350 1440.190 142.890 ;
        RECT 1.810 135.050 1440.190 139.350 ;
      LAYER Pwell ;
        RECT 1.810 131.510 106.270 135.050 ;
      LAYER Nwell ;
        RECT 106.270 131.510 1440.190 135.050 ;
        RECT 1.810 127.210 1440.190 131.510 ;
      LAYER Pwell ;
        RECT 1.810 123.670 106.270 127.210 ;
      LAYER Nwell ;
        RECT 106.270 123.670 1440.190 127.210 ;
        RECT 1.810 119.370 1440.190 123.670 ;
      LAYER Pwell ;
        RECT 1.810 115.830 106.270 119.370 ;
      LAYER Nwell ;
        RECT 106.270 115.830 1440.190 119.370 ;
        RECT 1.810 111.530 1440.190 115.830 ;
      LAYER Pwell ;
        RECT 1.810 107.990 106.270 111.530 ;
      LAYER Nwell ;
        RECT 106.270 107.990 1440.190 111.530 ;
        RECT 1.810 103.690 1440.190 107.990 ;
      LAYER Pwell ;
        RECT 1.810 100.150 106.270 103.690 ;
      LAYER Nwell ;
        RECT 106.270 100.150 1440.190 103.690 ;
        RECT 1.810 95.850 1440.190 100.150 ;
      LAYER Pwell ;
        RECT 1.810 92.310 106.270 95.850 ;
      LAYER Nwell ;
        RECT 106.270 92.310 1440.190 95.850 ;
        RECT 1.810 88.010 1440.190 92.310 ;
      LAYER Pwell ;
        RECT 1.810 84.470 106.270 88.010 ;
      LAYER Nwell ;
        RECT 106.270 84.470 1440.190 88.010 ;
        RECT 1.810 80.170 1440.190 84.470 ;
      LAYER Pwell ;
        RECT 1.810 76.630 106.270 80.170 ;
      LAYER Nwell ;
        RECT 106.270 76.630 1440.190 80.170 ;
        RECT 1.810 72.330 1440.190 76.630 ;
      LAYER Pwell ;
        RECT 1.810 68.790 106.270 72.330 ;
      LAYER Nwell ;
        RECT 106.270 68.790 1440.190 72.330 ;
        RECT 1.810 64.490 1440.190 68.790 ;
      LAYER Pwell ;
        RECT 1.810 60.950 106.270 64.490 ;
      LAYER Nwell ;
        RECT 106.270 60.950 1440.190 64.490 ;
        RECT 1.810 56.650 1440.190 60.950 ;
      LAYER Pwell ;
        RECT 1.810 53.110 106.270 56.650 ;
      LAYER Nwell ;
        RECT 106.270 53.110 1440.190 56.650 ;
        RECT 1.810 48.810 1440.190 53.110 ;
      LAYER Pwell ;
        RECT 1.810 45.270 106.270 48.810 ;
      LAYER Nwell ;
        RECT 106.270 45.270 1440.190 48.810 ;
        RECT 1.810 40.970 1440.190 45.270 ;
      LAYER Pwell ;
        RECT 1.810 37.430 106.270 40.970 ;
      LAYER Nwell ;
        RECT 106.270 37.430 1440.190 40.970 ;
        RECT 1.810 33.130 1440.190 37.430 ;
      LAYER Pwell ;
        RECT 1.810 29.590 106.270 33.130 ;
      LAYER Nwell ;
        RECT 106.270 29.590 1440.190 33.130 ;
        RECT 1.810 25.290 1440.190 29.590 ;
      LAYER Pwell ;
        RECT 1.810 21.750 106.270 25.290 ;
      LAYER Nwell ;
        RECT 106.270 21.750 1440.190 25.290 ;
        RECT 1.810 17.450 1440.190 21.750 ;
      LAYER Pwell ;
        RECT 1.810 13.910 106.270 17.450 ;
      LAYER Nwell ;
        RECT 106.270 13.910 1440.190 17.450 ;
        RECT 1.810 9.610 1440.190 13.910 ;
      LAYER Pwell ;
        RECT 1.810 7.410 106.270 9.610 ;
      LAYER Nwell ;
        RECT 106.270 7.410 1440.190 9.610 ;
        RECT 1.810 4.170 1440.190 7.410 ;
      LAYER Metal1 ;
        RECT 2.240 4.300 1439.760 733.340 ;
      LAYER Metal2 ;
        RECT 6.860 0.650 1420.020 736.310 ;
      LAYER Metal3 ;
        RECT 6.810 0.700 1420.070 736.260 ;
      LAYER Metal4 ;
        RECT 17.500 735.660 32.310 736.310 ;
        RECT 33.210 735.660 39.590 736.310 ;
        RECT 40.490 735.660 46.870 736.310 ;
        RECT 47.770 735.660 54.150 736.310 ;
        RECT 55.050 735.660 61.430 736.310 ;
        RECT 62.330 735.660 68.710 736.310 ;
        RECT 69.610 735.660 75.990 736.310 ;
        RECT 76.890 735.660 83.270 736.310 ;
        RECT 84.170 735.660 90.550 736.310 ;
        RECT 91.450 735.660 97.830 736.310 ;
        RECT 98.730 735.660 105.110 736.310 ;
        RECT 106.010 735.660 112.390 736.310 ;
        RECT 113.290 735.660 119.670 736.310 ;
        RECT 120.570 735.660 126.950 736.310 ;
        RECT 127.850 735.660 134.230 736.310 ;
        RECT 135.130 735.660 141.510 736.310 ;
        RECT 142.410 735.660 148.790 736.310 ;
        RECT 149.690 735.660 156.070 736.310 ;
        RECT 156.970 735.660 163.350 736.310 ;
        RECT 164.250 735.660 170.630 736.310 ;
        RECT 171.530 735.660 177.910 736.310 ;
        RECT 178.810 735.660 185.190 736.310 ;
        RECT 186.090 735.660 192.470 736.310 ;
        RECT 193.370 735.660 199.750 736.310 ;
        RECT 200.650 735.660 207.030 736.310 ;
        RECT 207.930 735.660 214.310 736.310 ;
        RECT 215.210 735.660 221.590 736.310 ;
        RECT 222.490 735.660 228.870 736.310 ;
        RECT 229.770 735.660 236.150 736.310 ;
        RECT 237.050 735.660 243.430 736.310 ;
        RECT 244.330 735.660 250.710 736.310 ;
        RECT 251.610 735.660 257.990 736.310 ;
        RECT 258.890 735.660 265.270 736.310 ;
        RECT 266.170 735.660 272.550 736.310 ;
        RECT 273.450 735.660 279.830 736.310 ;
        RECT 280.730 735.660 287.110 736.310 ;
        RECT 288.010 735.660 294.390 736.310 ;
        RECT 295.290 735.660 301.670 736.310 ;
        RECT 302.570 735.660 308.950 736.310 ;
        RECT 309.850 735.660 316.230 736.310 ;
        RECT 317.130 735.660 323.510 736.310 ;
        RECT 324.410 735.660 330.790 736.310 ;
        RECT 331.690 735.660 338.070 736.310 ;
        RECT 338.970 735.660 1379.780 736.310 ;
        RECT 17.500 733.640 1379.780 735.660 ;
        RECT 17.500 7.240 20.340 733.640 ;
        RECT 24.140 7.240 25.240 733.640 ;
        RECT 29.040 7.240 70.340 733.640 ;
        RECT 74.140 7.240 75.240 733.640 ;
        RECT 79.040 676.410 120.340 733.640 ;
        RECT 124.140 677.340 125.240 733.640 ;
        RECT 129.040 677.340 1379.780 733.640 ;
        RECT 124.140 676.410 1379.780 677.340 ;
        RECT 79.040 667.380 1379.780 676.410 ;
        RECT 79.040 7.240 128.980 667.380 ;
        RECT 17.500 0.650 128.980 7.240 ;
        RECT 131.180 0.650 132.280 667.380 ;
        RECT 134.480 0.650 204.580 667.380 ;
        RECT 206.780 0.650 207.880 667.380 ;
        RECT 210.080 0.650 304.580 667.380 ;
        RECT 306.780 0.650 307.880 667.380 ;
        RECT 310.080 0.650 404.580 667.380 ;
        RECT 406.780 0.650 407.880 667.380 ;
        RECT 410.080 0.650 485.700 667.380 ;
        RECT 487.900 0.650 489.000 667.380 ;
        RECT 491.200 0.650 585.700 667.380 ;
        RECT 587.900 0.650 589.000 667.380 ;
        RECT 591.200 0.650 685.700 667.380 ;
        RECT 687.900 0.650 689.000 667.380 ;
        RECT 691.200 0.650 766.820 667.380 ;
        RECT 769.020 0.650 770.120 667.380 ;
        RECT 772.320 0.650 866.820 667.380 ;
        RECT 869.020 0.650 870.120 667.380 ;
        RECT 872.320 0.650 966.820 667.380 ;
        RECT 969.020 0.650 970.120 667.380 ;
        RECT 972.320 0.650 1047.940 667.380 ;
        RECT 1050.140 0.650 1051.240 667.380 ;
        RECT 1053.440 0.650 1147.940 667.380 ;
        RECT 1150.140 0.650 1151.240 667.380 ;
        RECT 1153.440 0.650 1247.940 667.380 ;
        RECT 1250.140 0.650 1251.240 667.380 ;
        RECT 1253.440 0.650 1329.060 667.380 ;
        RECT 1331.260 0.650 1332.360 667.380 ;
        RECT 1334.560 0.650 1379.780 667.380 ;
  END
END tt_um_fabulous_gf_0p3_3v3
END LIBRARY

